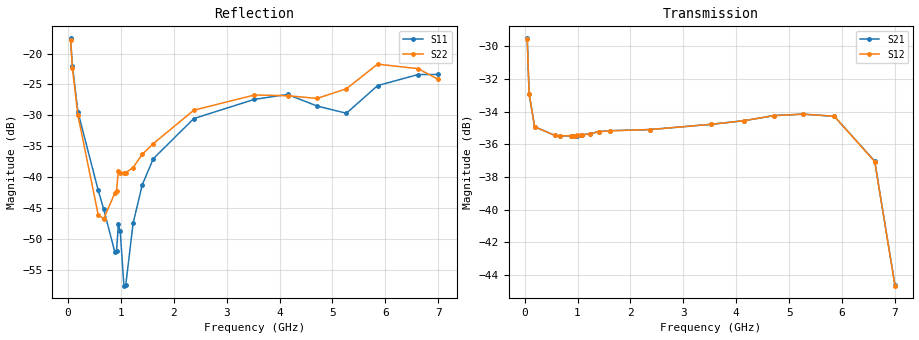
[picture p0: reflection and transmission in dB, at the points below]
! Integrated Device Technology
! Corporate Headquarters
! 6024 Silver Creek Valley Road
! San Jose, CA 95138  USA
! Phone:  1-408-284-8200
! Toll Free:  1-800-223-1366
! Webpage:  http://www.idt.com/
! Timing and RF Division
! 515 Groton Road, Suite 102
! Westford, MA 01886-6024
! Device:  F2258
! Description: Voltage Variable RF Attenuator
! Frequency:  50.0 -  6000.00 MHz
! Package:  3x3 mm Thin QFN Plastic Package: 16 pin
! Ports:  2 RF, 2 DC
!  Pin  1  = NC
!  Pin  2  = NC
!  Pin  3  = RF2  = Port 2
!  Pin  4  = GND
!  Pin  5  = Vdd
!  Pin  6  = NC
!  Pin  7  = VCTRL
!  Pin  8  = NC
!  Pin  9  = GND
!  Pin 10  = RF1  = Port 1
!  Pin 11  = NC
!  Pin 12  = NC
!  Pin 13  = NC
!  Pin 14  = NC
!  Pin 15  = NC
!  Pin 16  = NC
! Vcntrl:  2.380 Volts
! Vdd:  +3.300 Volts
! Current:  1.146 mA
! Data:  The device was measured on a the F2258 evaluation board which has
!  individual transmission lines to the RF pins.  Data was collected
!  using a calibrated network analyzer.  The evaluation board was
!  de-embedded using a TRL calibration technique.
!  The reference plane is the edge of the package pin.
! Misc:  SN 10
!  Action Tracker AT0285
! Date Measured:  2014-12-10
! Date:  2016-01-13  MJV
! Note:
!  Integrated Device Technology supplies this data as a sample of measured
!  data at the package pin for this product.  Your particular data for this
!  product may vary.
!  Data was taken at 25 degrees C.
!  Integrated Device Technology reserves the right to change this data at anytime.
!Freq_(GHz)  S11M_(dB)  S11P_(deg)  S21M_(dB)  S21P_(deg)  S12M_(dB)  S12P_(deg)  S22M_(dB)  S22P_(deg)
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# GHz S dB R 50
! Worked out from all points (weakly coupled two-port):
!   201 points, 50 MHz to 7 GHz, reference 50 ohm
!   highest |S21| = -29.53 dB at 50 MHz (marker M1); lowest = -44.6 dB at 7 GHz (marker M2)
!   lowest |S11| = -57.5 dB at 1.058 GHz (marker M3), VSWR 1.00, Z = 49.9 + j0.0562 ohm
!   |S11| at or under -10 dB: start of sweep to end of sweep
!   |S22| runs from -46.7 to -17.8 dB; largest |S21 - S12| = 8.3e-05
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0.05  -17.55 -111.0  -29.53 -68.6  -29.54 -68.7  -17.78 -111.6
0.08475  -21.98 -107.4  -32.91 -48.9  -32.91 -48.9  -22.42 -108.3
0.189  -29.43 -109.5  -34.93 -24.8  -34.93 -24.8  -29.99 -112.0
0.57125  -42.09 -124.7  -35.46 -10.4  -35.46 -10.4  -46.04 -170.0
0.6755  -45.15 -131.8  -35.48 -9.4  -35.48 -9.4  -46.74 153.1
0.884  -52.02 166.4  -35.48 -8.4  -35.48 -8.4  -42.61 126.0
0.91875  -51.91 150.5  -35.47 -8.3  -35.48 -8.3  -42.18 123.6
0.9535  -47.56 -163.0  -35.49 -8.2  -35.48 -8.2  -39.00 126.9
0.98825  -48.71 -174.8  -35.47 -8.1  -35.46 -8.1  -39.34 124.8
1.05775  -57.54 154.9  -35.45 -7.9  -35.45 -7.9  -39.39 111.5
1.0925  -57.46 119.6  -35.43 -7.8  -35.43 -7.9  -39.26 107.4
1.2315  -47.46 47.0  -35.35 -7.8  -35.36 -7.9  -38.44 85.9
1.40525  -41.22 34.0  -35.23 -8.5  -35.23 -8.5  -36.28 71.1
1.61375  -37.00 32.7  -35.17 -9.5  -35.18 -9.5  -34.57 57.3
2.37825  -30.52 48.1  -35.10 -13.1  -35.10 -13.1  -29.17 45.6
3.525  -27.41 91.6  -34.78 -19.5  -34.78 -19.5  -26.71 68.8
4.1505  -26.62 105.0  -34.56 -23.9  -34.56 -23.9  -26.82 76.3
4.7065  -28.48 95.7  -34.25 -28.6  -34.25 -28.6  -27.26 59.9
5.2625  -29.66 54.4  -34.16 -34.7  -34.16 -34.7  -25.70 22.7
5.85325  -25.19 29.8  -34.29 -45.4  -34.29 -45.3  -21.72 -1.6
6.61775  -23.40 49.7  -37.03 -68.5  -37.06 -68.6  -22.45 -43.5
7  -23.38 84.5  -44.60 -61.5  -44.64 -61.0  -24.18 -130.2
